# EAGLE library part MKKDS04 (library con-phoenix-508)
PHOENIX

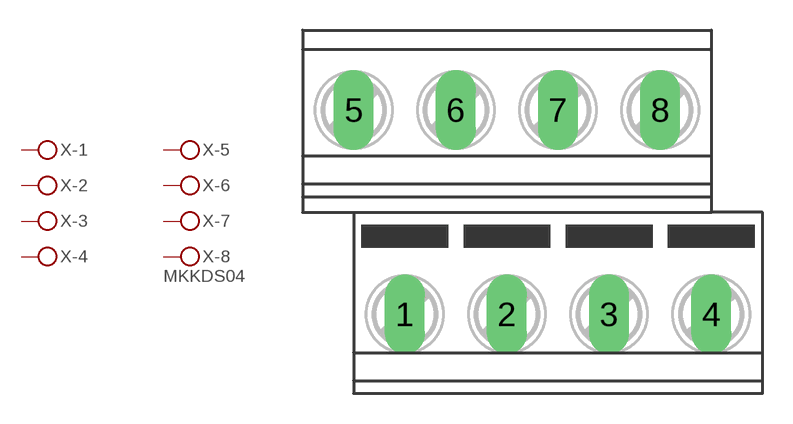
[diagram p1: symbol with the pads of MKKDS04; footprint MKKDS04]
Designator prefix X; gates -1=KL -2=KL -3=KL -4=KL -5=KL -6=KL -7=KL -8=KLV

## MKKDS04 (OC_FARNELL: unknown; OC_NEWARK: unknown)  [MKKDS04]
1  -1:KL  pas
2  -2:KL  pas
3  -3:KL  pas
4  -4:KL  pas
5  -5:KL  pas
6  -6:KL  pas
7  -7:KL  pas
8  -8:KL  pas

## Footprint MKKDS04 (pad centres in mm)
PHOENIX MKKDSN 1,5/ 8-5,08 Source: http://eshop.phoenixcontact.com .. 1726202.pdf
drill 1.321 long: 1 -6.35,-5.08; 2 -1.27,-5.08; 3 3.81,-5.08; 4 8.89,-5.08; 5 -8.89,5.08; 6 -3.81,5.08; 7 1.27,5.08; 8 6.35,5.08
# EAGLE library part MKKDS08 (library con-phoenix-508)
PHOENIX

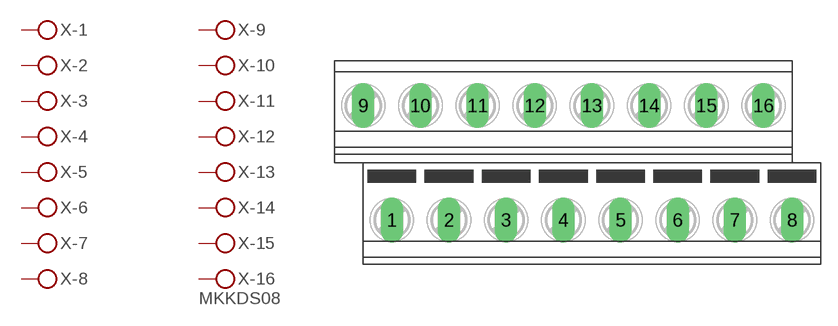
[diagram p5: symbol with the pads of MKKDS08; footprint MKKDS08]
Designator prefix X; gates -1=KL -2=KL -3=KL -4=KL -5=KL -6=KL -7=KL -8=KL -9=KL -10=KL -11=KL -12=KL -13=KL -14=KL -15=KL -16=KLV

## MKKDS08 (OC_FARNELL: unknown; OC_NEWARK: unknown)  [MKKDS08]
1  -1:KL  pas
2  -2:KL  pas
3  -3:KL  pas
4  -4:KL  pas
5  -5:KL  pas
6  -6:KL  pas
7  -7:KL  pas
8  -8:KL  pas
9  -9:KL  pas
10  -10:KL  pas
11  -11:KL  pas
12  -12:KL  pas
13  -13:KL  pas
14  -14:KL  pas
15  -15:KL  pas
16  -16:KL  pas

## Footprint MKKDS08 (pad centres in mm)
PHOENIX MKKDSN 1,5/ 8-5,08 Source: http://eshop.phoenixcontact.com .. 1726202.pdf
drill 1.321 long: 1 -16.51,-5.08; 2 -11.43,-5.08; 3 -6.35,-5.08; 4 -1.27,-5.08; 5 3.81,-5.08; 6 8.89,-5.08; 7 13.97,-5.08; 8 19.05,-5.08; 9 -19.05,5.08; 10 -13.97,5.08; 11 -8.89,5.08; 12 -3.81,5.08; 13 1.27,5.08; 14 6.35,5.08; 15 11.43,5.08; 16 16.51,5.08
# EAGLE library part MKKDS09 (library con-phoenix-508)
PHOENIX

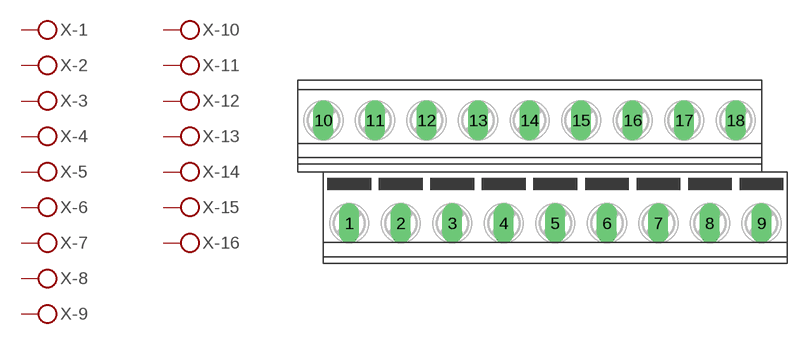
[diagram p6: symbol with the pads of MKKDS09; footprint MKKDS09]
Designator prefix X; gates -1=KL -2=KL -3=KL -4=KL -5=KL -6=KL -7=KL -8=KL -9=KL -10=KL -11=KL -12=KL -13=KL -14=KL -15=KL -16=KL -17=KL -18=KLV

## MKKDS09 (OC_FARNELL: unknown; OC_NEWARK: unknown)  [MKKDS09]
1  -1:KL  pas
2  -2:KL  pas
3  -3:KL  pas
4  -4:KL  pas
5  -5:KL  pas
6  -6:KL  pas
7  -7:KL  pas
8  -8:KL  pas
9  -9:KL  pas
10  -10:KL  pas
11  -11:KL  pas
12  -12:KL  pas
13  -13:KL  pas
14  -14:KL  pas
15  -15:KL  pas
16  -16:KL  pas
17  -17:KL  pas
18  -18:KL  pas

## Footprint MKKDS09 (pad centres in mm)
PHOENIX MKKDSN 1,5/ 8-5,08 Source: http://eshop.phoenixcontact.com .. 1726202.pdf
drill 1.321 long: 1 -19.05,-5.08; 2 -13.97,-5.08; 3 -8.89,-5.08; 4 -3.81,-5.08; 5 1.27,-5.08; 6 6.35,-5.08; 7 11.43,-5.08; 8 16.51,-5.08; 9 21.59,-5.08; 10 -21.59,5.08; 11 -16.51,5.08; 12 -11.43,5.08; 13 -6.35,5.08; 14 -1.27,5.08; 15 3.81,5.08; 16 8.89,5.08; 17 13.97,5.08; 18 19.05,5.08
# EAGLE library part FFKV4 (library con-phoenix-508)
PHOENIX

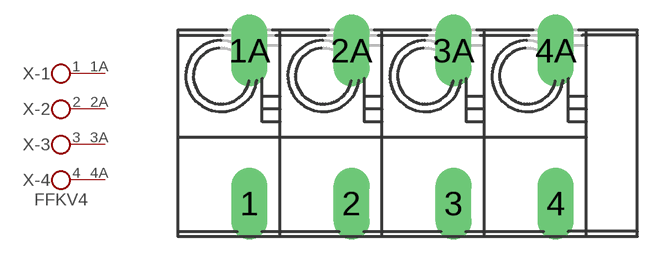
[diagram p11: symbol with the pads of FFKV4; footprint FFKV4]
Designator prefix X; gates -1=KL2 -2=KL2 -3=KL2 -4=KL2V

## FFKV4 (OC_FARNELL: unknown; OC_NEWARK: unknown)  [FFKV4]
1  -1:1  pas
1A  -1:2  pas
2  -2:1  pas
2A  -2:2  pas
3  -3:1  pas
3A  -3:2  pas
4  -4:1  pas
4A  -4:2  pas

## Footprint FFKV4 (pad centres in mm)
PHOENIX
drill 1.194 long: 1 -7.62,-3.81; 1A -7.62,3.81; 2 -2.54,-3.81; 2A -2.54,3.81; 3 2.54,-3.81; 3A 2.54,3.81; 4 7.62,-3.81; 4A 7.62,3.81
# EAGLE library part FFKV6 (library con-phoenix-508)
PHOENIX

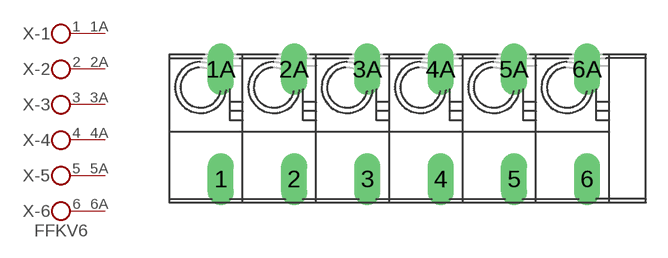
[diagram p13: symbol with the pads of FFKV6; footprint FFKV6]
Designator prefix X; gates -1=KL2 -2=KL2 -3=KL2 -4=KL2 -5=KL2 -6=KL2V

## FFKV6 (OC_FARNELL: unknown; OC_NEWARK: unknown)  [FFKV6]
1  -1:1  pas
1A  -1:2  pas
2  -2:1  pas
2A  -2:2  pas
3  -3:1  pas
3A  -3:2  pas
4  -4:1  pas
4A  -4:2  pas
5  -5:1  pas
5A  -5:2  pas
6  -6:1  pas
6A  -6:2  pas

## Footprint FFKV6 (pad centres in mm)
PHOENIX
drill 1.194 long: 1 -12.7,-3.81; 1A -12.7,3.81; 2 -7.62,-3.81; 2A -7.62,3.81; 3 -2.54,-3.81; 3A -2.54,3.81; 4 2.54,-3.81; 4A 2.54,3.81; 5 7.62,-3.81; 5A 7.62,3.81; 6 12.7,-3.81; 6A 12.7,3.81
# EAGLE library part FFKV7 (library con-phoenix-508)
PHOENIX

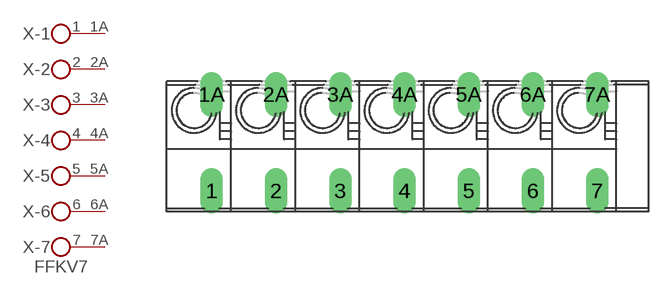
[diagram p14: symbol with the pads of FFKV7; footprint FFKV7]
Designator prefix X; gates -1=KL2 -2=KL2 -3=KL2 -4=KL2 -5=KL2 -6=KL2 -7=KL2V

## FFKV7 (OC_FARNELL: unknown; OC_NEWARK: unknown)  [FFKV7]
1  -1:1  pas
1A  -1:2  pas
2  -2:1  pas
2A  -2:2  pas
3  -3:1  pas
3A  -3:2  pas
4  -4:1  pas
4A  -4:2  pas
5  -5:1  pas
5A  -5:2  pas
6  -6:1  pas
6A  -6:2  pas
7  -7:1  pas
7A  -7:2  pas

## Footprint FFKV7 (pad centres in mm)
PHOENIX
drill 1.194 long: 1 -15.24,-3.81; 1A -15.24,3.81; 2 -10.16,-3.81; 2A -10.16,3.81; 3 -5.08,-3.81; 3A -5.08,3.81; 4 0,-3.81; 4A 0,3.81; 5 5.08,-3.81; 5A 5.08,3.81; 6 10.16,-3.81; 6A 10.16,3.81; 7 15.24,-3.81; 7A 15.24,3.81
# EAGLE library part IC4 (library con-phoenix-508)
PHOENIX

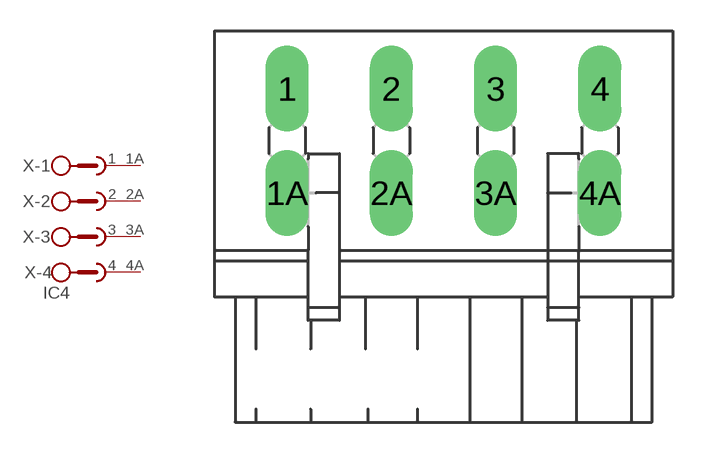
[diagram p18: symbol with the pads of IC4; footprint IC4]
Designator prefix X; gates -1=SKB2 -2=SKB2 -3=SKB2 -4=SKB2V

## IC4 (OC_FARNELL: unknown; OC_NEWARK: unknown)  [IC4]
1  -1:1  pas
1A  -1:2  pas
2  -2:1  pas
2A  -2:2  pas
3  -3:1  pas
3A  -3:2  pas
4  -4:1  pas
4A  -4:2  pas

## Footprint IC4 (pad centres in mm)
PHOENIX
drill 1.397 long: 1 -7.62,2.54; 1A -7.62,-2.54; 2 -2.54,2.54; 2A -2.54,-2.54; 3 2.54,2.54; 3A 2.54,-2.54; 4 7.62,2.54; 4A 7.62,-2.54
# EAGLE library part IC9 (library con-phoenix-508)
PHOENIX

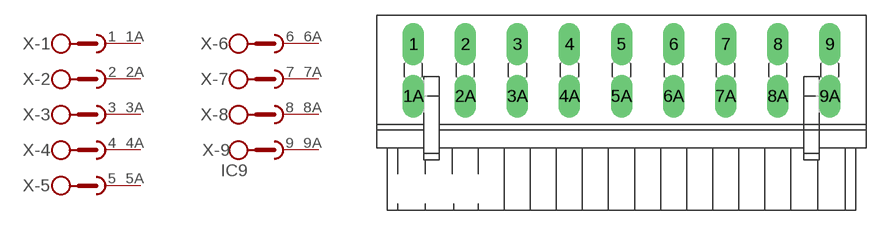
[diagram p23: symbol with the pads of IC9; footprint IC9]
Designator prefix X; gates -1=SKB2 -2=SKB2 -3=SKB2 -4=SKB2 -5=SKB2 -6=SKB2 -7=SKB2 -8=SKB2 -9=SKB2V

## IC9 (OC_FARNELL: unknown; OC_NEWARK: unknown)  [IC9]
1  -1:1  pas
1A  -1:2  pas
2  -2:1  pas
2A  -2:2  pas
3  -3:1  pas
3A  -3:2  pas
4  -4:1  pas
4A  -4:2  pas
5  -5:1  pas
5A  -5:2  pas
6  -6:1  pas
6A  -6:2  pas
7  -7:1  pas
7A  -7:2  pas
8  -8:1  pas
8A  -8:2  pas
9  -9:1  pas
9A  -9:2  pas

## Footprint IC9 (pad centres in mm)
PHOENIX
drill 1.397 long: 1 -20.32,2.54; 1A -20.32,-2.54; 2 -15.24,2.54; 2A -15.24,-2.54; 3 -10.16,2.54; 3A -10.16,-2.54; 4 -5.08,2.54; 4A -5.08,-2.54; 5 0,2.54; 5A 0,-2.54; 6 5.08,2.54; 6A 5.08,-2.54; 7 10.16,2.54; 7A 10.16,-2.54; 8 15.24,2.54; 8A 15.24,-2.54; 9 20.32,2.54; 9A 20.32,-2.54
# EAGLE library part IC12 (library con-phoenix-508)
PHOENIX

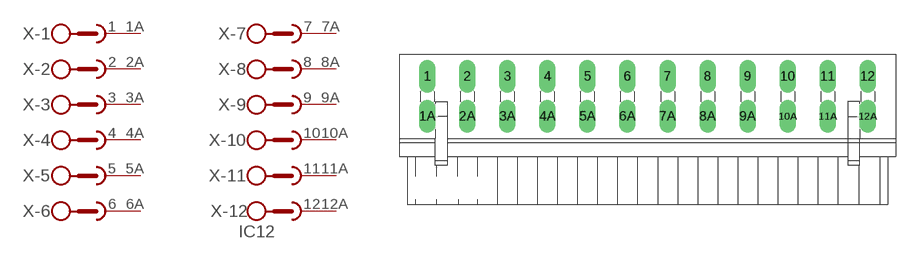
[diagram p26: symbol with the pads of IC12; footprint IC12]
Designator prefix X; gates -1=SKB2 -2=SKB2 -3=SKB2 -4=SKB2 -5=SKB2 -6=SKB2 -7=SKB2 -8=SKB2 -9=SKB2 -10=SKB2 -11=SKB2 -12=SKB2V

## IC12 (OC_FARNELL: unknown; OC_NEWARK: unknown)  [IC12]
1  -1:1  pas
1A  -1:2  pas
2  -2:1  pas
2A  -2:2  pas
3  -3:1  pas
3A  -3:2  pas
4  -4:1  pas
4A  -4:2  pas
5  -5:1  pas
5A  -5:2  pas
6  -6:1  pas
6A  -6:2  pas
7  -7:1  pas
7A  -7:2  pas
8  -8:1  pas
8A  -8:2  pas
9  -9:1  pas
9A  -9:2  pas
10  -10:1  pas
10A  -10:2  pas
11  -11:1  pas
11A  -11:2  pas
12  -12:1  pas
12A  -12:2  pas

## Footprint IC12 (pad centres in mm)
PHOENIX
drill 1.397 long: 1 -27.94,2.54; 1A -27.94,-2.54; 2 -22.86,2.54; 2A -22.86,-2.54; 3 -17.78,2.54; 3A -17.78,-2.54; 4 -12.7,2.54; 4A -12.7,-2.54; 5 -7.62,2.54; 5A -7.62,-2.54; 6 -2.54,2.54; 6A -2.54,-2.54; 7 2.54,2.54; 7A 2.54,-2.54; 8 7.62,2.54; 8A 7.62,-2.54; 9 12.7,2.54; 9A 12.7,-2.54; 10 17.78,2.54; 10A 17.78,-2.54; 11 22.86,2.54; 11A 22.86,-2.54; 12 27.94,2.54; 12A 27.94,-2.54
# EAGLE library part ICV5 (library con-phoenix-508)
PHOENIX

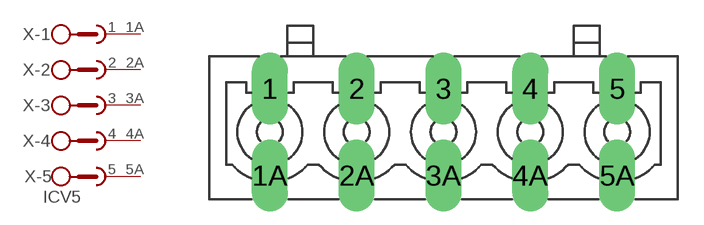
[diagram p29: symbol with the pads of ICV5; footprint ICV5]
Designator prefix X; gates -1=SKB2 -2=SKB2 -3=SKB2 -4=SKB2 -5=SKB2V

## ICV5 (OC_FARNELL: unknown; OC_NEWARK: unknown)  [ICV5]
1  -1:1  pas
1A  -1:2  pas
2  -2:1  pas
2A  -2:2  pas
3  -3:1  pas
3A  -3:2  pas
4  -4:1  pas
4A  -4:2  pas
5  -5:1  pas
5A  -5:2  pas

## Footprint ICV5 (pad centres in mm)
PHOENIX
drill 1.397 long: 1 -10.16,2.54; 1A -10.16,-2.54; 2 -5.08,2.54; 2A -5.08,-2.54; 3 0,2.54; 3A 0,-2.54; 4 5.08,2.54; 4A 5.08,-2.54; 5 10.16,2.54; 5A 10.16,-2.54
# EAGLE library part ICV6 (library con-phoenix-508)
PHOENIX

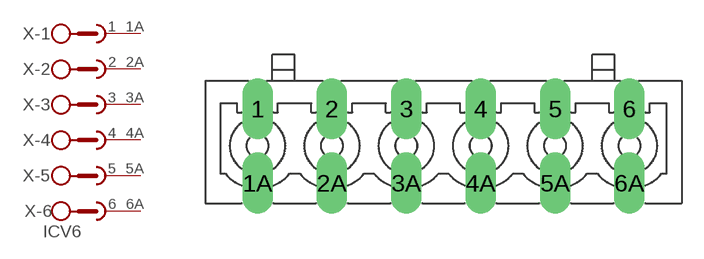
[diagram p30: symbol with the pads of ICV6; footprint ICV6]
Designator prefix X; gates -1=SKB2 -2=SKB2 -3=SKB2 -4=SKB2 -5=SKB2 -6=SKB2V

## ICV6 (OC_FARNELL: unknown; OC_NEWARK: unknown)  [ICV6]
1  -1:1  pas
1A  -1:2  pas
2  -2:1  pas
2A  -2:2  pas
3  -3:1  pas
3A  -3:2  pas
4  -4:1  pas
4A  -4:2  pas
5  -5:1  pas
5A  -5:2  pas
6  -6:1  pas
6A  -6:2  pas

## Footprint ICV6 (pad centres in mm)
PHOENIX
drill 1.397 long: 1 -12.7,2.54; 1A -12.7,-2.54; 2 -7.62,2.54; 2A -7.62,-2.54; 3 -2.54,2.54; 3A -2.54,-2.54; 4 2.54,2.54; 4A 2.54,-2.54; 5 7.62,2.54; 5A 7.62,-2.54; 6 12.7,2.54; 6A 12.7,-2.54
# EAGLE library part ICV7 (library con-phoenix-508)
PHOENIX

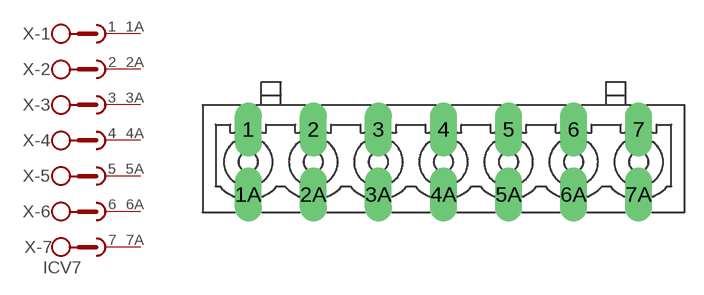
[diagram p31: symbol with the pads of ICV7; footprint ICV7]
Designator prefix X; gates -1=SKB2 -2=SKB2 -3=SKB2 -4=SKB2 -5=SKB2 -6=SKB2 -7=SKB2V

## ICV7 (OC_FARNELL: unknown; OC_NEWARK: unknown)  [ICV7]
1  -1:1  pas
1A  -1:2  pas
2  -2:1  pas
2A  -2:2  pas
3  -3:1  pas
3A  -3:2  pas
4  -4:1  pas
4A  -4:2  pas
5  -5:1  pas
5A  -5:2  pas
6  -6:1  pas
6A  -6:2  pas
7  -7:1  pas
7A  -7:2  pas

## Footprint ICV7 (pad centres in mm)
PHOENIX
drill 1.397 long: 1 -15.24,2.54; 1A -15.24,-2.54; 2 -10.16,2.54; 2A -10.16,-2.54; 3 -5.08,2.54; 3A -5.08,-2.54; 4 0,2.54; 4A 0,-2.54; 5 5.08,2.54; 5A 5.08,-2.54; 6 10.16,2.54; 6A 10.16,-2.54; 7 15.24,2.54; 7A 15.24,-2.54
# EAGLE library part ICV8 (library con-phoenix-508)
PHOENIX

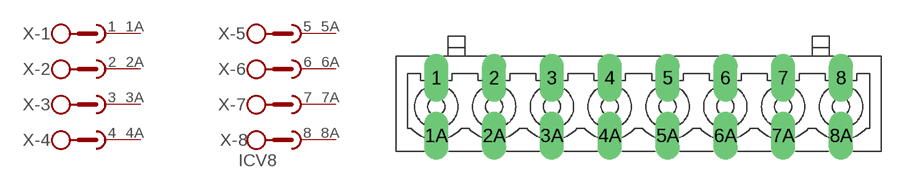
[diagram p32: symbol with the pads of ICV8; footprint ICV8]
Designator prefix X; gates -1=SKB2 -2=SKB2 -3=SKB2 -4=SKB2 -5=SKB2 -6=SKB2 -7=SKB2 -8=SKB2V

## ICV8 (OC_FARNELL: unknown; OC_NEWARK: unknown)  [ICV8]
1  -1:1  pas
1A  -1:2  pas
2  -2:1  pas
2A  -2:2  pas
3  -3:1  pas
3A  -3:2  pas
4  -4:1  pas
4A  -4:2  pas
5  -5:1  pas
5A  -5:2  pas
6  -6:1  pas
6A  -6:2  pas
7  -7:1  pas
7A  -7:2  pas
8  -8:1  pas
8A  -8:2  pas

## Footprint ICV8 (pad centres in mm)
PHOENIX
drill 1.397 long: 1 -17.78,2.54; 1A -17.78,-2.54; 2 -12.7,2.54; 2A -12.7,-2.54; 3 -7.62,2.54; 3A -7.62,-2.54; 4 -2.54,2.54; 4A -2.54,-2.54; 5 2.54,2.54; 5A 2.54,-2.54; 6 7.62,2.54; 6A 7.62,-2.54; 7 12.7,2.54; 7A 12.7,-2.54; 8 17.78,2.54; 8A 17.78,-2.54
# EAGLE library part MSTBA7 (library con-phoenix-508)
PHOENIX

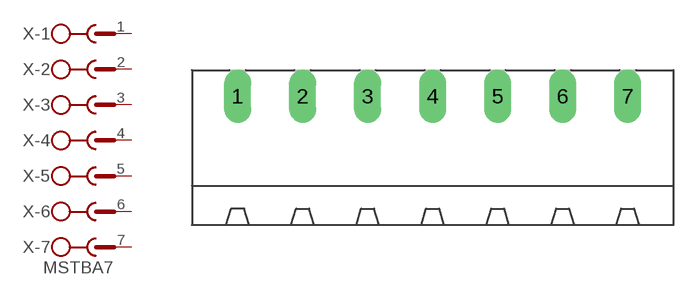
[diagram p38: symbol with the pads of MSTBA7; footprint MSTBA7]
Designator prefix X; gates -1=SK -2=SK -3=SK -4=SK -5=SK -6=SK -7=SKV

## MSTBA7 (OC_FARNELL: unknown; OC_NEWARK: unknown)  [MSTBA7]
1  -1:1  pas
2  -2:1  pas
3  -3:1  pas
4  -4:1  pas
5  -5:1  pas
6  -6:1  pas
7  -7:1  pas

## Footprint MSTBA7 (pad centres in mm)
PHOENIX
drill 1.397 long: 1 -15.24,5.08; 2 -10.16,5.08; 3 -5.08,5.08; 4 0,5.08; 5 5.08,5.08; 6 10.16,5.08; 7 15.24,5.08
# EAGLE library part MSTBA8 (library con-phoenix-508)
PHOENIX

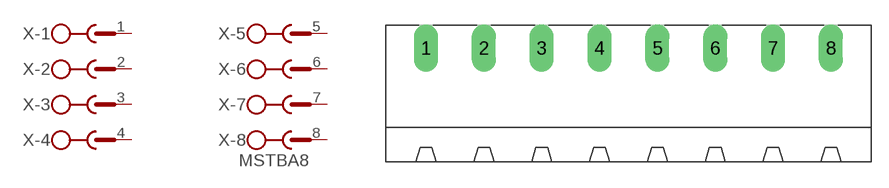
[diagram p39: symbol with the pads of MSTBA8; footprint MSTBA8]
Designator prefix X; gates -1=SK -2=SK -3=SK -4=SK -5=SK -6=SK -7=SK -8=SKV

## MSTBA8 (MF: FARNELL; MPN: 1757307; OC_FARNELL: 3705225; OC_NEWARK: 71C4166)  [MSTBA8]
1  -1:1  pas
2  -2:1  pas
3  -3:1  pas
4  -4:1  pas
5  -5:1  pas
6  -6:1  pas
7  -7:1  pas
8  -8:1  pas

## Footprint MSTBA8 (pad centres in mm)
PHOENIX
drill 1.397 long: 1 -17.78,5.08; 2 -12.7,5.08; 3 -7.62,5.08; 4 -2.54,5.08; 5 2.54,5.08; 6 7.62,5.08; 7 12.7,5.08; 8 17.78,5.08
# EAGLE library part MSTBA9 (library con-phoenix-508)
PHOENIX

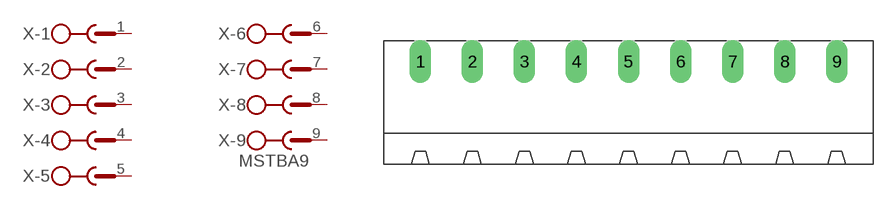
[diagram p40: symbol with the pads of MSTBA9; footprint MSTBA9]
Designator prefix X; gates -1=SK -2=SK -3=SK -4=SK -5=SK -6=SK -7=SK -8=SK -9=SKV

## MSTBA9 (MF: FARNELL; MPN: 1757310; OC_FARNELL: 3705237; OC_NEWARK: 71C4167)  [MSTBA9]
1  -1:1  pas
2  -2:1  pas
3  -3:1  pas
4  -4:1  pas
5  -5:1  pas
6  -6:1  pas
7  -7:1  pas
8  -8:1  pas
9  -9:1  pas

## Footprint MSTBA9 (pad centres in mm)
PHOENIX
drill 1.397 long: 1 -20.32,5.08; 2 -15.24,5.08; 3 -10.16,5.08; 4 -5.08,5.08; 5 0,5.08; 6 5.08,5.08; 7 10.16,5.08; 8 15.24,5.08; 9 20.32,5.08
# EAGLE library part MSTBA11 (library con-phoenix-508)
PHOENIX

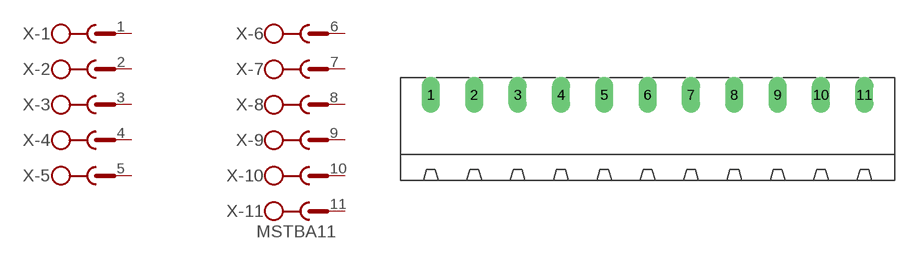
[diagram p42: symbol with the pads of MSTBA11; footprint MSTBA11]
Designator prefix X; gates -1=SK -2=SK -3=SK -4=SK -5=SK -6=SK -7=SK -8=SK -9=SK -10=SK -11=SKV

## MSTBA11 (OC_FARNELL: unknown; OC_NEWARK: unknown)  [MSTBA11]
1  -1:1  pas
2  -2:1  pas
3  -3:1  pas
4  -4:1  pas
5  -5:1  pas
6  -6:1  pas
7  -7:1  pas
8  -8:1  pas
9  -9:1  pas
10  -10:1  pas
11  -11:1  pas

## Footprint MSTBA11 (pad centres in mm)
PHOENIX
drill 1.397 long: 1 -25.4,5.08; 2 -20.32,5.08; 3 -15.24,5.08; 4 -10.16,5.08; 5 -5.08,5.08; 6 0,5.08; 7 5.08,5.08; 8 10.16,5.08; 9 15.24,5.08; 10 20.32,5.08; 11 25.4,5.08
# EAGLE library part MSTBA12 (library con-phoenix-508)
PHOENIX

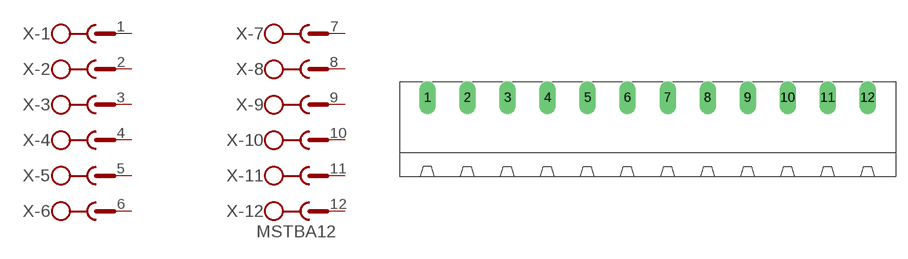
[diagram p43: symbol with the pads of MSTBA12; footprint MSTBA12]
Designator prefix X; gates -1=SK -2=SK -3=SK -4=SK -5=SK -6=SK -7=SK -8=SK -9=SK -10=SK -11=SK -12=SKV

## MSTBA12 (MPN: 1757349; OC_FARNELL: 3705250; OC_NEWARK: 71C4169)  [MSTBA12]
1  -1:1  pas
2  -2:1  pas
3  -3:1  pas
4  -4:1  pas
5  -5:1  pas
6  -6:1  pas
7  -7:1  pas
8  -8:1  pas
9  -9:1  pas
10  -10:1  pas
11  -11:1  pas
12  -12:1  pas

## Footprint MSTBA12 (pad centres in mm)
PHOENIX
drill 1.397 long: 1 -27.94,5.08; 2 -22.86,5.08; 3 -17.78,5.08; 4 -12.7,5.08; 5 -7.62,5.08; 6 -2.54,5.08; 7 2.54,5.08; 8 7.62,5.08; 9 12.7,5.08; 10 17.78,5.08; 11 22.86,5.08; 12 27.94,5.08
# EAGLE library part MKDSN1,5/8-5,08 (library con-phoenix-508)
MKDSN 1,5/ 8-5,08 Printklemme Nennstrom: 13,5 A Nennspannung: 250 V Rastermaß: 5,08 mm Polzahl: 8 Anschlussart: Schraubanschluss Montage: Löten Anschlussrichtung Leiter/Platine: 0 ° Artikelnummer: 1729186 Source: http://eshop.phoenixcontact.com .. 1729186.pdf

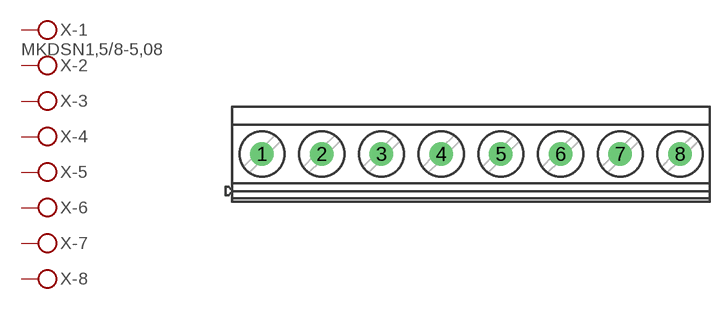
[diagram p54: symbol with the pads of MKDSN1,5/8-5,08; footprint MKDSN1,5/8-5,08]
Designator prefix X; gates -1=KLV -2=KL -3=KL -4=KL -5=KL -6=KL -7=KL -8=KL

## MKDSN1,5/8-5,08 (MPN: SMKDSN1,5/8-5,08; OC_FARNELL: 1792911; OC_NEWARK: 70R0304)  [MKDSN1,5/8-5,08]
1  -1:KL  pas
2  -2:KL  pas
3  -3:KL  pas
4  -4:KL  pas
5  -5:KL  pas
6  -6:KL  pas
7  -7:KL  pas
8  -8:KL  pas

## Footprint MKDSN1,5/8-5,08 (pad centres in mm)
MKDSN 1,5/ 8-5,08 Printklemme Nennstrom: 13,5 A Nennspannung: 250 V Rastermaß: 5,08 mm Polzahl: 8 Anschlussart: Schraubanschluss Montage: Löten Anschlussrichtung Leiter/Platine: 0 ° Artikelnummer: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
drill 1.3 pad 2 round: 1 -17.801,0.025; 2 -12.721,0.025; 3 -7.641,0.025; 4 -2.561,0.025; 5 2.519,0.025; 6 7.599,0.025; 7 12.679,0.025; 8 17.759,0.025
